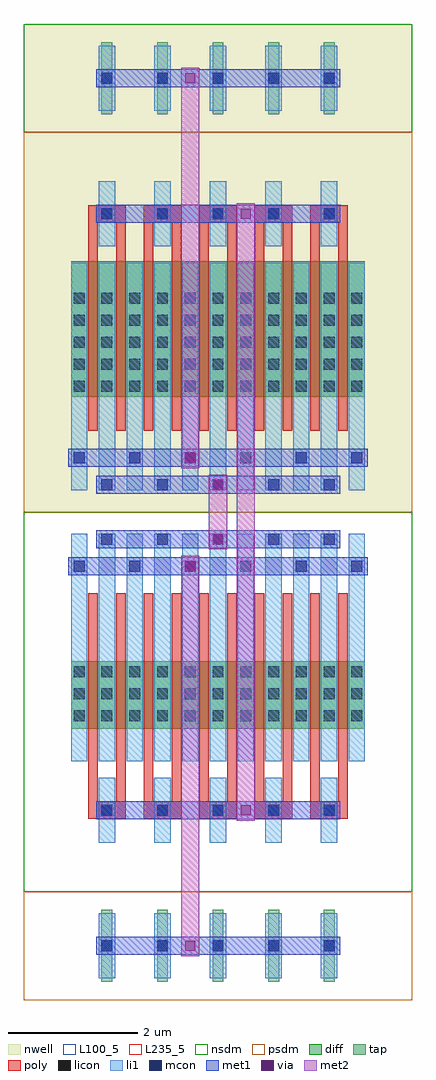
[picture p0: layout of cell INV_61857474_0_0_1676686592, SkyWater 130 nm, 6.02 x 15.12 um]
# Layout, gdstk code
from math import pi, radians
import gdstk
lib = gdstk.Library(unit=1e-6, precision=1e-09)
def R(c, l, rs):  # rectangles x0, y0, x1, y1
    for r in rs: c.add(gdstk.rectangle(r[:2], r[2:], *l))
def A(c, l, x, y, w, h, nx, ny, dx, dy):  # array of equal rectangles
    R(c, l, [(x+i*dx, y+j*dy, x+i*dx+w, y+j*dy+h) for i in range(nx) for j in range(ny)])
def P(c, l, *ps):  # polygons
    for p in ps: c.add(gdstk.Polygon(p, *l))
nwell = (64, 20)
diff = (65, 20)
tap = (65, 44)
poly = (66, 20)
licon = (66, 44)
li1 = (67, 20)
mcon = (67, 44)
met1 = (68, 20)
via = (68, 44)
met2 = (69, 20)
nsdm = (93, 44)
psdm = (94, 20)
L100_5 = (100, 5)
L235_5 = (235, 5)

nmos_s_79666698_x5_y1_16 = lib.new_cell('NMOS_S_79666698_X5_Y1_1676686589_1676686592')
R(nmos_s_79666698_x5_y1_16, diff, [(0.735,2.31,5.285,3.36)])
A(nmos_s_79666698_x5_y1_16, tap, 1.205, 6.16, 0.17, 1.12, 5, 1, 0.86, 0)
A(nmos_s_79666698_x5_y1_16, poly, 1, 1.26, 0.15, 3.36, 10, 1, 0.43, 0)
A(nmos_s_79666698_x5_y1_16, poly, 1, 4.485, 0.58, 0.27, 5, 1, 0.86, 0)
A(nmos_s_79666698_x5_y1_16, licon, 0.775, 2.39, 0.17, 0.17, 3, 3, 0.43, 0.34)
A(nmos_s_79666698_x5_y1_16, licon, 1.635, 2.39, 0.17, 0.17, 3, 3, 0.43, 0.34)
A(nmos_s_79666698_x5_y1_16, licon, 2.495, 2.39, 0.17, 0.17, 3, 3, 0.43, 0.34)
A(nmos_s_79666698_x5_y1_16, licon, 3.355, 2.39, 0.17, 0.17, 3, 3, 0.43, 0.34)
A(nmos_s_79666698_x5_y1_16, licon, 4.215, 2.39, 0.17, 0.17, 3, 3, 0.43, 0.34)
A(nmos_s_79666698_x5_y1_16, licon, 1.205, 4.535, 0.17, 0.17, 5, 2, 0.86, 2.1)
A(nmos_s_79666698_x5_y1_16, li1, 0.735, 0.335, 0.25, 3.53, 11, 1, 0.43, 0)
A(nmos_s_79666698_x5_y1_16, li1, 1.165, 4.115, 0.25, 1.01, 5, 2, 0.86, 2.1)
A(nmos_s_79666698_x5_y1_16, mcon, 1.205, 0.335, 0.17, 0.17, 5, 2, 0.86, 4.2)
A(nmos_s_79666698_x5_y1_16, mcon, 0.775, 0.755, 0.17, 0.17, 6, 1, 0.86, 0)
A(nmos_s_79666698_x5_y1_16, mcon, 1.205, 6.635, 0.17, 0.17, 5, 1, 0.86, 0)
R(nmos_s_79666698_x5_y1_16, met1, [(1.12,0.28,4.9,0.56), (0.69,0.7,5.33,0.98), (1.12,4.48,4.9,4.76), (1.12,6.58,4.9,6.86)])
R(nmos_s_79666698_x5_y1_16, via, [(3.365,0.765,3.515,0.915), (3.365,6.645,3.515,6.795)])
R(nmos_s_79666698_x5_y1_16, met2, [(3.3,0.68,3.58,6.88)])
R(nmos_s_79666698_x5_y1_16, nsdm, [(0,0,6.02,5.88)])
R(nmos_s_79666698_x5_y1_16, psdm, [(0,5.88,6.02,7.56)])
R(nmos_s_79666698_x5_y1_16, L100_5, [(0,0,6.02,7.56)])

pmos_s_49267959_x5_y1_16 = lib.new_cell('PMOS_S_49267959_X5_Y1_1676686590_1676686592')
R(pmos_s_49267959_x5_y1_16, nwell, [(0,0,6.02,7.56)])
R(pmos_s_49267959_x5_y1_16, diff, [(0.735,1.785,5.285,3.885)])
A(pmos_s_49267959_x5_y1_16, tap, 1.205, 6.16, 0.17, 1.12, 5, 1, 0.86, 0)
A(pmos_s_49267959_x5_y1_16, poly, 1, 1.26, 0.15, 3.36, 10, 1, 0.43, 0)
A(pmos_s_49267959_x5_y1_16, poly, 1, 4.485, 0.58, 0.27, 5, 1, 0.86, 0)
A(pmos_s_49267959_x5_y1_16, licon, 0.775, 1.865, 0.17, 0.17, 3, 5, 0.43, 0.34)
A(pmos_s_49267959_x5_y1_16, licon, 1.635, 1.865, 0.17, 0.17, 3, 5, 0.43, 0.34)
A(pmos_s_49267959_x5_y1_16, licon, 2.495, 1.865, 0.17, 0.17, 3, 5, 0.43, 0.34)
A(pmos_s_49267959_x5_y1_16, licon, 3.355, 1.865, 0.17, 0.17, 3, 5, 0.43, 0.34)
A(pmos_s_49267959_x5_y1_16, licon, 4.215, 1.865, 0.17, 0.17, 3, 5, 0.43, 0.34)
A(pmos_s_49267959_x5_y1_16, licon, 1.205, 4.535, 0.17, 0.17, 5, 2, 0.86, 2.1)
A(pmos_s_49267959_x5_y1_16, li1, 0.735, 0.335, 0.25, 3.53, 11, 1, 0.43, 0)
A(pmos_s_49267959_x5_y1_16, li1, 1.165, 4.115, 0.25, 1.01, 5, 2, 0.86, 2.1)
A(pmos_s_49267959_x5_y1_16, mcon, 1.205, 0.335, 0.17, 0.17, 5, 2, 0.86, 4.2)
A(pmos_s_49267959_x5_y1_16, mcon, 0.775, 0.755, 0.17, 0.17, 6, 1, 0.86, 0)
A(pmos_s_49267959_x5_y1_16, mcon, 1.205, 6.635, 0.17, 0.17, 5, 1, 0.86, 0)
R(pmos_s_49267959_x5_y1_16, met1, [(1.12,0.28,4.9,0.56), (0.69,0.7,5.33,0.98), (1.12,4.48,4.9,4.76), (1.12,6.58,4.9,6.86)])
R(pmos_s_49267959_x5_y1_16, via, [(3.365,0.765,3.515,0.915), (3.365,6.645,3.515,6.795)])
R(pmos_s_49267959_x5_y1_16, met2, [(3.3,0.68,3.58,6.88)])
R(pmos_s_49267959_x5_y1_16, nsdm, [(0,5.88,6.02,7.56)])
R(pmos_s_49267959_x5_y1_16, psdm, [(0,0,6.02,5.88)])
R(pmos_s_49267959_x5_y1_16, L100_5, [(0,0,6.02,7.56)])

inv_61857474_0_0_1676686 = lib.new_cell('INV_61857474_0_0_1676686592')
R(inv_61857474_0_0_1676686, met1, [(3.28,2.8,3.6,3.08), (3.28,2.8,3.6,3.08), (2.85,7,3.17,7.28), (2.85,7,3.17,7.28), (2.85,7.84,3.17,8.12), (2.85,7.84,3.17,8.12), (3.28,12.04,3.6,12.32), (3.28,12.04,3.6,12.32)])
P(inv_61857474_0_0_1676686, met1, [(0,0),(0,0),(0,0),(0,0)],
  [(0,0),(0,0),(0,0),(0,0)],
  [(0,0),(0,0),(0,0),(0,0)],
  [(0,0),(0,0),(0,0),(0,0)])
R(inv_61857474_0_0_1676686, via, [(3.365,2.865,3.515,3.015), (3.365,2.865,3.515,3.015), (2.935,7.065,3.085,7.215), (2.935,7.065,3.085,7.215), (2.935,7.905,3.085,8.055), (2.935,7.905,3.085,8.055), (3.365,12.105,3.515,12.255), (3.365,12.105,3.515,12.255)])
R(inv_61857474_0_0_1676686, met2, [(3.3,2.78,3.58,3.1), (3.3,2.78,3.58,3.1), (3.3,2.94,3.58,12.18), (2.87,6.98,3.15,7.3), (2.87,6.98,3.15,7.3), (2.87,7.14,3.15,7.98), (2.87,7.82,3.15,8.14), (2.87,7.82,3.15,8.14), (3.3,12.02,3.58,12.34), (3.3,12.02,3.58,12.34)])
P(inv_61857474_0_0_1676686, met2, [(0,0),(0,0),(0,0),(0,0)],
  [(0,0),(0,0),(0,0),(0,0)])
R(inv_61857474_0_0_1676686, L235_5, [(0,0,6.02,15.12)])
inv_61857474_0_0_1676686.add(gdstk.Reference(nmos_s_79666698_x5_y1_16, (6.02,7.56), rotation=pi))
inv_61857474_0_0_1676686.add(gdstk.Reference(pmos_s_49267959_x5_y1_16, (6.02,7.56), rotation=pi, x_reflection=True))

lib.write_gds('INV_61857474_0_0_1676686592.gds')
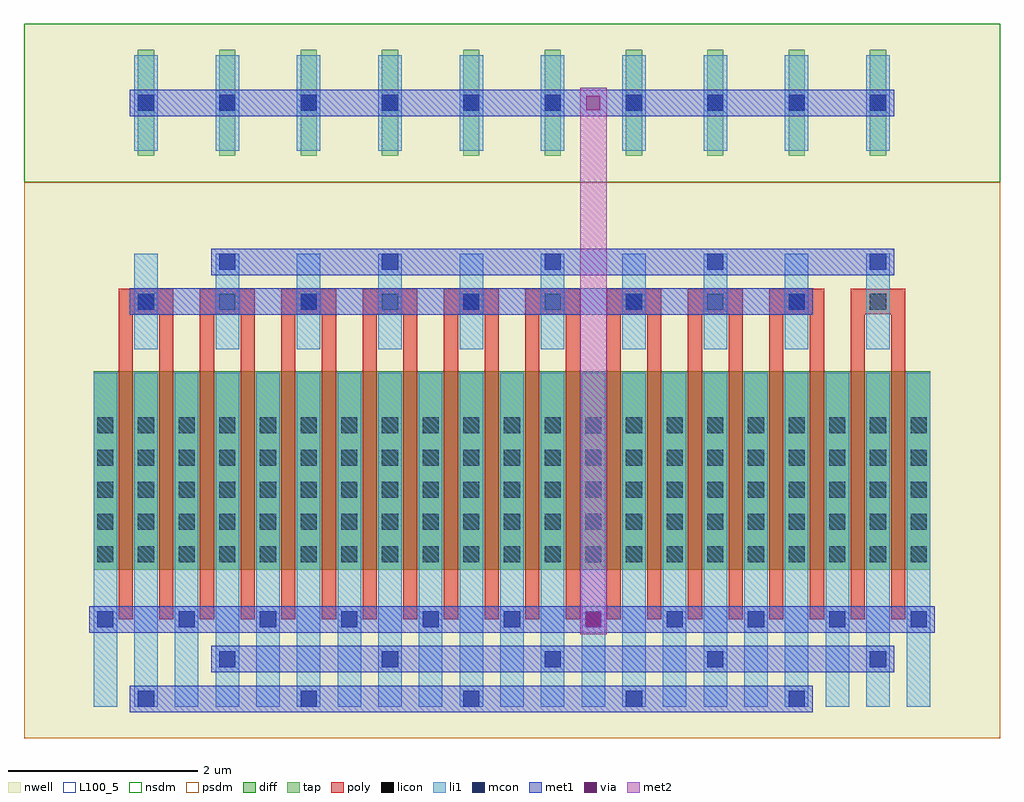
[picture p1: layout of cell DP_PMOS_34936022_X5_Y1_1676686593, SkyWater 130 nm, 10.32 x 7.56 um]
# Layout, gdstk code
import gdstk
lib = gdstk.Library(unit=1e-6, precision=1e-09)
def R(c, l, rs):  # rectangles x0, y0, x1, y1
    for r in rs: c.add(gdstk.rectangle(r[:2], r[2:], *l))
def A(c, l, x, y, w, h, nx, ny, dx, dy):  # array of equal rectangles
    R(c, l, [(x+i*dx, y+j*dy, x+i*dx+w, y+j*dy+h) for i in range(nx) for j in range(ny)])
nwell = (64, 20)
diff = (65, 20)
tap = (65, 44)
poly = (66, 20)
licon = (66, 44)
li1 = (67, 20)
mcon = (67, 44)
met1 = (68, 20)
via = (68, 44)
met2 = (69, 20)
nsdm = (93, 44)
psdm = (94, 20)
L100_5 = (100, 5)

dp_pmos_34936022_x5_y1_1 = lib.new_cell('DP_PMOS_34936022_X5_Y1_1676686593')
R(dp_pmos_34936022_x5_y1_1, nwell, [(0,0,10.32,7.56)])
R(dp_pmos_34936022_x5_y1_1, diff, [(0.735,1.785,9.585,3.885)])
A(dp_pmos_34936022_x5_y1_1, tap, 1.205, 6.16, 0.17, 1.12, 10, 1, 0.86, 0)
A(dp_pmos_34936022_x5_y1_1, poly, 1, 1.26, 0.15, 3.36, 20, 1, 0.43, 0)
A(dp_pmos_34936022_x5_y1_1, poly, 1, 4.485, 0.58, 0.27, 10, 1, 0.86, 0)
A(dp_pmos_34936022_x5_y1_1, licon, 0.775, 1.865, 0.17, 0.17, 3, 5, 0.43, 0.34)
A(dp_pmos_34936022_x5_y1_1, licon, 1.635, 1.865, 0.17, 0.17, 3, 5, 0.43, 0.34)
A(dp_pmos_34936022_x5_y1_1, licon, 2.495, 1.865, 0.17, 0.17, 3, 5, 0.43, 0.34)
A(dp_pmos_34936022_x5_y1_1, licon, 3.355, 1.865, 0.17, 0.17, 3, 5, 0.43, 0.34)
A(dp_pmos_34936022_x5_y1_1, licon, 4.215, 1.865, 0.17, 0.17, 3, 5, 0.43, 0.34)
A(dp_pmos_34936022_x5_y1_1, licon, 5.075, 1.865, 0.17, 0.17, 3, 5, 0.43, 0.34)
A(dp_pmos_34936022_x5_y1_1, licon, 5.935, 1.865, 0.17, 0.17, 3, 5, 0.43, 0.34)
A(dp_pmos_34936022_x5_y1_1, licon, 6.795, 1.865, 0.17, 0.17, 3, 5, 0.43, 0.34)
A(dp_pmos_34936022_x5_y1_1, licon, 7.655, 1.865, 0.17, 0.17, 3, 5, 0.43, 0.34)
A(dp_pmos_34936022_x5_y1_1, licon, 8.515, 1.865, 0.17, 0.17, 3, 5, 0.43, 0.34)
A(dp_pmos_34936022_x5_y1_1, licon, 1.205, 4.535, 0.17, 0.17, 10, 2, 0.86, 2.1)
A(dp_pmos_34936022_x5_y1_1, li1, 0.735, 0.335, 0.25, 3.53, 21, 1, 0.43, 0)
A(dp_pmos_34936022_x5_y1_1, li1, 1.165, 4.115, 0.25, 1.01, 10, 2, 0.86, 2.1)
A(dp_pmos_34936022_x5_y1_1, mcon, 1.205, 0.335, 0.17, 0.17, 5, 2, 1.72, 4.2)
A(dp_pmos_34936022_x5_y1_1, mcon, 2.065, 0.755, 0.17, 0.17, 5, 2, 1.72, 4.2)
A(dp_pmos_34936022_x5_y1_1, mcon, 0.775, 1.175, 0.17, 0.17, 11, 1, 0.86, 0)
A(dp_pmos_34936022_x5_y1_1, mcon, 1.205, 6.635, 0.17, 0.17, 10, 1, 0.86, 0)
R(dp_pmos_34936022_x5_y1_1, met1, [(1.12,0.28,8.34,0.56), (1.98,0.7,9.2,0.98), (0.69,1.12,9.63,1.4), (1.12,4.48,8.34,4.76), (1.98,4.9,9.2,5.18), (1.12,6.58,9.2,6.86)])
R(dp_pmos_34936022_x5_y1_1, via, [(5.945,1.185,6.095,1.335), (5.945,6.645,6.095,6.795)])
R(dp_pmos_34936022_x5_y1_1, met2, [(5.88,1.1,6.16,6.88)])
R(dp_pmos_34936022_x5_y1_1, nsdm, [(0,5.88,10.32,7.56)])
R(dp_pmos_34936022_x5_y1_1, psdm, [(0,0,10.32,5.88)])
R(dp_pmos_34936022_x5_y1_1, L100_5, [(0,0,10.32,7.56)])

lib.write_gds('DP_PMOS_34936022_X5_Y1_1676686593.gds')
